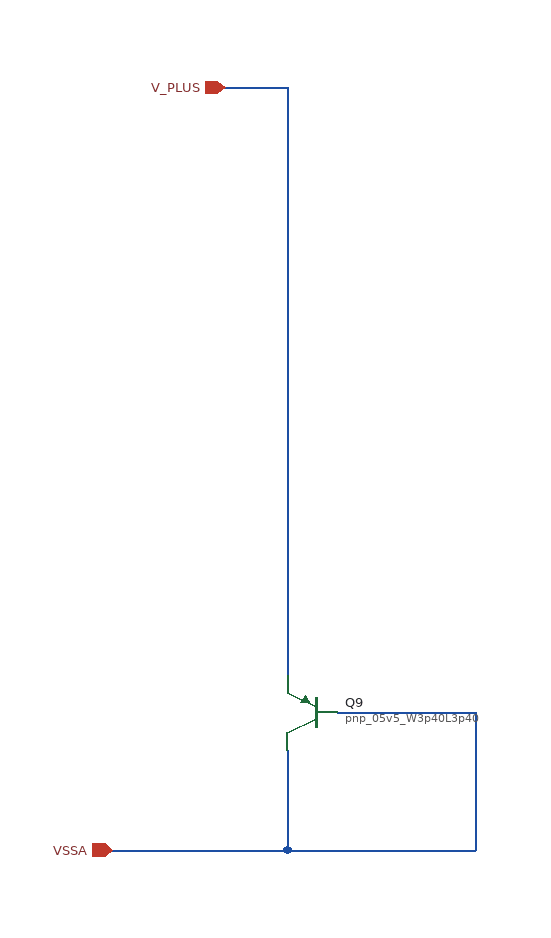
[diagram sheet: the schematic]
v {xschem version=3.4.8RC file_version=1.3}
G {}
K {}
V {}
S {}
F {}
E {}
N 1420 -320 1420 -280 {lab=V_PLUS}
N 1420 -220 1420 -140 {lab=VSSA}
N 1280 -140 1420 -140 {lab=VSSA}
N 1460 -250 1570 -250 {lab=VSSA}
N 1570 -250 1570 -140 {lab=VSSA}
N 1420 -140 1570 -140 {lab=VSSA}
N 1420 -750 1420 -610 {lab=V_PLUS}
N 1420 -610 1420 -550 {lab=V_PLUS}
N 1420 -550 1420 -320 {lab=V_PLUS}
N 1370 -750 1420 -750 {lab=V_PLUS}
C {/usr/local/share/pdk/sky130B/libs.tech/xschem/sky130_fd_pr/pnp_05v5.sym} 1440 -250 0 1 {name=Q9
model=pnp_05v5_W3p40L3p40
m=1
spiceprefix=X
}
C {ipin.sym} 1280 -140 0 0 {name=p2 lab=VSSA}
C {ipin.sym} 1370 -750 0 0 {name=p1 lab=V_PLUS}
